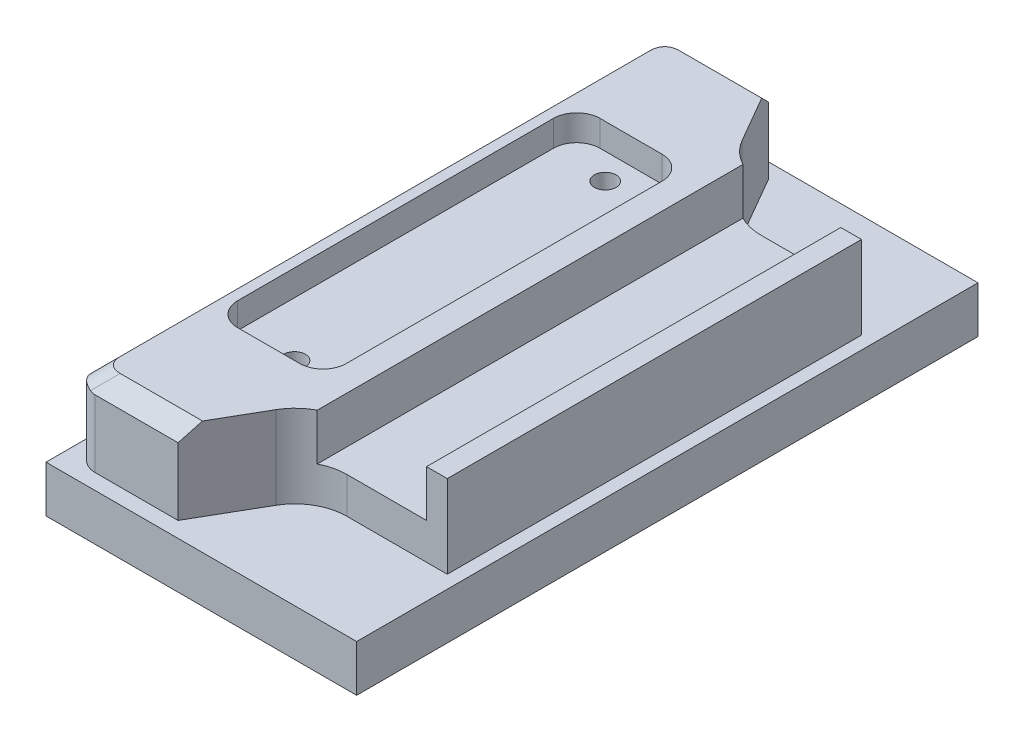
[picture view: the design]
ISO-10303-21;
HEADER;
FILE_DESCRIPTION(('STEP AP214'),'2;1');
FILE_NAME('part.step','',(''),(''),'','','');
FILE_SCHEMA(('AUTOMOTIVE_DESIGN { 1 0 10303 214 1 1 1 1 }'));
ENDSEC;
DATA;
#1=APPLICATION_CONTEXT('core data for automotive mechanical design processes');
#2=APPLICATION_PROTOCOL_DEFINITION('international standard','automotive_design',2000,#1);
#3=PRODUCT_CONTEXT('',#1,'mechanical');
#4=PRODUCT('Part','Part','',(#3));
#5=PRODUCT_RELATED_PRODUCT_CATEGORY('part','',(#4));
#6=PRODUCT_DEFINITION_FORMATION('','',#4);
#7=PRODUCT_DEFINITION_CONTEXT('part definition',#1,'design');
#8=PRODUCT_DEFINITION('design','',#6,#7);
#9=PRODUCT_DEFINITION_SHAPE('','',#8);
#10=(LENGTH_UNIT() NAMED_UNIT(*) SI_UNIT(.MILLI.,.METRE.));
#11=(NAMED_UNIT(*) PLANE_ANGLE_UNIT() SI_UNIT($,.RADIAN.));
#12=(NAMED_UNIT(*) SI_UNIT($,.STERADIAN.) SOLID_ANGLE_UNIT());
#13=UNCERTAINTY_MEASURE_WITH_UNIT(LENGTH_MEASURE(1.E-05),#10,'distance_accuracy_value','');
#14=(GEOMETRIC_REPRESENTATION_CONTEXT(3) GLOBAL_UNCERTAINTY_ASSIGNED_CONTEXT((#13)) GLOBAL_UNIT_ASSIGNED_CONTEXT((#10,
#11,#12)) REPRESENTATION_CONTEXT('',''));
#15=CARTESIAN_POINT('',(0.,0.,0.));
#16=DIRECTION('',(0.,0.,1.));
#17=DIRECTION('',(1.,0.,0.));
#18=AXIS2_PLACEMENT_3D('',#15,#16,#17);
#19=CARTESIAN_POINT('',(0.,16.,57.));
#20=DIRECTION('',(0.,-1.,0.));
#21=DIRECTION('',(1.,0.,0.));
#22=AXIS2_PLACEMENT_3D('',#19,#20,#21);
#23=PLANE('',#22);
#24=DIRECTION('',(1.,0.,0.));
#25=VECTOR('',#24,1.);
#26=CARTESIAN_POINT('',(55.,16.,-40.));
#27=LINE('',#26,#25);
#28=CARTESIAN_POINT('',(51.,16.,-40.));
#29=VERTEX_POINT('',#28);
#30=CARTESIAN_POINT('',(55.,16.,-40.));
#31=VERTEX_POINT('',#30);
#32=EDGE_CURVE('E363',#29,#31,#27,.T.);
#33=ORIENTED_EDGE('',*,*,#32,.F.);
#34=DIRECTION('',(0.,0.,1.));
#35=VECTOR('',#34,1.);
#36=CARTESIAN_POINT('',(51.,16.,-57.));
#37=LINE('',#36,#35);
#38=CARTESIAN_POINT('',(51.,16.,40.));
#39=VERTEX_POINT('',#38);
#40=EDGE_CURVE('E294',#29,#39,#37,.T.);
#41=ORIENTED_EDGE('',*,*,#40,.T.);
#42=DIRECTION('',(-1.,0.,0.));
#43=VECTOR('',#42,1.);
#44=CARTESIAN_POINT('',(55.,16.,40.));
#45=LINE('',#44,#43);
#46=CARTESIAN_POINT('',(55.,16.,40.));
#47=VERTEX_POINT('',#46);
#48=EDGE_CURVE('E375',#47,#39,#45,.T.);
#49=ORIENTED_EDGE('',*,*,#48,.F.);
#50=DIRECTION('',(0.,0.,-1.));
#51=VECTOR('',#50,1.);
#52=CARTESIAN_POINT('',(55.,16.,57.));
#53=LINE('',#52,#51);
#54=EDGE_CURVE('E399',#47,#31,#53,.T.);
#55=ORIENTED_EDGE('',*,*,#54,.T.);
#56=EDGE_LOOP('',(#33,#41,#49,#55));
#57=FACE_BOUND('',#56,.T.);
#58=ADVANCED_FACE('F30',(#57),#23,.F.);
#59=CARTESIAN_POINT('',(0.,0.,57.));
#60=DIRECTION('',(1.,0.,0.));
#61=DIRECTION('',(0.,0.,-1.));
#62=AXIS2_PLACEMENT_3D('',#59,#60,#61);
#63=PLANE('',#62);
#64=DIRECTION('',(0.,0.,-1.));
#65=VECTOR('',#64,1.);
#66=CARTESIAN_POINT('',(0.,0.,57.));
#67=LINE('',#66,#65);
#68=CARTESIAN_POINT('',(0.,0.,53.));
#69=VERTEX_POINT('',#68);
#70=CARTESIAN_POINT('',(0.,0.,-53.));
#71=VERTEX_POINT('',#70);
#72=EDGE_CURVE('E405',#69,#71,#67,.T.);
#73=ORIENTED_EDGE('',*,*,#72,.F.);
#74=DIRECTION('',(0.,-1.,0.));
#75=VECTOR('',#74,1.);
#76=CARTESIAN_POINT('',(0.,0.,53.));
#77=LINE('',#76,#75);
#78=CARTESIAN_POINT('',(0.,13.,53.));
#79=VERTEX_POINT('',#78);
#80=EDGE_CURVE('E461',#69,#79,#77,.F.);
#81=ORIENTED_EDGE('',*,*,#80,.T.);
#82=DIRECTION('',(0.,0.,-1.));
#83=VECTOR('',#82,1.);
#84=CARTESIAN_POINT('',(0.,13.,57.));
#85=LINE('',#84,#83);
#86=CARTESIAN_POINT('',(0.,13.,-53.));
#87=VERTEX_POINT('',#86);
#88=EDGE_CURVE('E419',#79,#87,#85,.T.);
#89=ORIENTED_EDGE('',*,*,#88,.T.);
#90=DIRECTION('',(0.,-1.,0.));
#91=VECTOR('',#90,1.);
#92=CARTESIAN_POINT('',(0.,0.,-53.));
#93=LINE('',#92,#91);
#94=EDGE_CURVE('E458',#87,#71,#93,.T.);
#95=ORIENTED_EDGE('',*,*,#94,.T.);
#96=EDGE_LOOP('',(#73,#81,#89,#95));
#97=FACE_BOUND('',#96,.T.);
#98=ADVANCED_FACE('F32',(#97),#63,.F.);
#99=CARTESIAN_POINT('',(55.,0.,57.));
#100=DIRECTION('',(-1.,0.,0.));
#101=DIRECTION('',(0.,0.,1.));
#102=AXIS2_PLACEMENT_3D('',#99,#100,#101);
#103=PLANE('',#102);
#104=DIRECTION('',(0.,0.,-1.));
#105=VECTOR('',#104,1.);
#106=CARTESIAN_POINT('',(55.,0.,57.));
#107=LINE('',#106,#105);
#108=CARTESIAN_POINT('',(55.,0.,40.));
#109=VERTEX_POINT('',#108);
#110=CARTESIAN_POINT('',(55.,0.,-40.));
#111=VERTEX_POINT('',#110);
#112=EDGE_CURVE('E402',#109,#111,#107,.T.);
#113=ORIENTED_EDGE('',*,*,#112,.T.);
#114=DIRECTION('',(0.,1.,0.));
#115=VECTOR('',#114,1.);
#116=CARTESIAN_POINT('',(55.,0.,-40.));
#117=LINE('',#116,#115);
#118=EDGE_CURVE('E372',#111,#31,#117,.T.);
#119=ORIENTED_EDGE('',*,*,#118,.T.);
#120=ORIENTED_EDGE('',*,*,#54,.F.);
#121=DIRECTION('',(0.,1.,0.));
#122=VECTOR('',#121,1.);
#123=CARTESIAN_POINT('',(55.,0.,40.));
#124=LINE('',#123,#122);
#125=EDGE_CURVE('E389',#109,#47,#124,.T.);
#126=ORIENTED_EDGE('',*,*,#125,.F.);
#127=EDGE_LOOP('',(#113,#119,#120,#126));
#128=FACE_BOUND('',#127,.T.);
#129=ADVANCED_FACE('F549',(#128),#103,.F.);
#130=DIRECTION('',(-1.,0.,0.));
#131=VECTOR('',#130,1.);
#132=CARTESIAN_POINT('',(26.,16.,-35.));
#133=LINE('',#132,#131);
#134=CARTESIAN_POINT('',(21.5,16.,-35.));
#135=VERTEX_POINT('',#134);
#136=CARTESIAN_POINT('',(9.49999999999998,16.,-35.));
#137=VERTEX_POINT('',#136);
#138=EDGE_CURVE('E339',#135,#137,#133,.T.);
#139=ORIENTED_EDGE('',*,*,#138,.F.);
#140=CARTESIAN_POINT('',(21.5,16.,-30.5));
#141=DIRECTION('',(0.,-1.,0.));
#142=DIRECTION('',(1.,0.,0.));
#143=AXIS2_PLACEMENT_3D('',#140,#141,#142);
#144=CIRCLE('',#143,4.5);
#145=CARTESIAN_POINT('',(26.,16.,-30.5));
#146=VERTEX_POINT('',#145);
#147=EDGE_CURVE('E53',#135,#146,#144,.T.);
#148=ORIENTED_EDGE('',*,*,#147,.T.);
#149=DIRECTION('',(0.,0.,-1.));
#150=VECTOR('',#149,1.);
#151=CARTESIAN_POINT('',(26.,16.,35.));
#152=LINE('',#151,#150);
#153=CARTESIAN_POINT('',(26.,16.,30.5));
#154=VERTEX_POINT('',#153);
#155=EDGE_CURVE('E337',#154,#146,#152,.T.);
#156=ORIENTED_EDGE('',*,*,#155,.F.);
#157=CARTESIAN_POINT('',(21.5,16.,30.5));
#158=DIRECTION('',(0.,-1.,0.));
#159=DIRECTION('',(1.,0.,0.));
#160=AXIS2_PLACEMENT_3D('',#157,#158,#159);
#161=CIRCLE('',#160,4.5);
#162=CARTESIAN_POINT('',(21.5,16.,35.));
#163=VERTEX_POINT('',#162);
#164=EDGE_CURVE('E526',#154,#163,#161,.T.);
#165=ORIENTED_EDGE('',*,*,#164,.T.);
#166=DIRECTION('',(1.,0.,0.));
#167=VECTOR('',#166,1.);
#168=CARTESIAN_POINT('',(26.,16.,35.));
#169=LINE('',#168,#167);
#170=CARTESIAN_POINT('',(9.49999999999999,16.,35.));
#171=VERTEX_POINT('',#170);
#172=EDGE_CURVE('E345',#171,#163,#169,.T.);
#173=ORIENTED_EDGE('',*,*,#172,.F.);
#174=CARTESIAN_POINT('',(9.49999999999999,16.,30.5));
#175=DIRECTION('',(0.,-1.,0.));
#176=DIRECTION('',(1.,0.,0.));
#177=AXIS2_PLACEMENT_3D('',#174,#175,#176);
#178=CIRCLE('',#177,4.5);
#179=CARTESIAN_POINT('',(4.99999999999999,16.,30.5));
#180=VERTEX_POINT('',#179);
#181=EDGE_CURVE('E521',#171,#180,#178,.T.);
#182=ORIENTED_EDGE('',*,*,#181,.T.);
#183=DIRECTION('',(0.,0.,1.));
#184=VECTOR('',#183,1.);
#185=CARTESIAN_POINT('',(4.99999999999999,16.,35.));
#186=LINE('',#185,#184);
#187=CARTESIAN_POINT('',(4.99999999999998,16.,-30.5));
#188=VERTEX_POINT('',#187);
#189=EDGE_CURVE('E342',#188,#180,#186,.T.);
#190=ORIENTED_EDGE('',*,*,#189,.F.);
#191=CARTESIAN_POINT('',(9.49999999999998,16.,-30.5));
#192=DIRECTION('',(0.,-1.,0.));
#193=DIRECTION('',(1.,0.,0.));
#194=AXIS2_PLACEMENT_3D('',#191,#192,#193);
#195=CIRCLE('',#194,4.5);
#196=EDGE_CURVE('E523',#188,#137,#195,.T.);
#197=ORIENTED_EDGE('',*,*,#196,.T.);
#198=EDGE_LOOP('',(#139,#148,#156,#165,#173,#182,#190,#197));
#199=FACE_BOUND('',#198,.T.);
#200=CARTESIAN_POINT('',(35.5884572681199,16.,50.));
#201=DIRECTION('',(0.,-1.,0.));
#202=DIRECTION('',(1.,0.,0.));
#203=AXIS2_PLACEMENT_3D('',#200,#201,#202);
#204=CIRCLE('',#203,10.);
#205=CARTESIAN_POINT('',(26.9282032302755,16.,45.));
#206=VERTEX_POINT('',#205);
#207=CARTESIAN_POINT('',(31.,16.,41.1148404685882));
#208=VERTEX_POINT('',#207);
#209=EDGE_CURVE('E443',#206,#208,#204,.T.);
#210=ORIENTED_EDGE('',*,*,#209,.T.);
#211=DIRECTION('',(0.,0.,1.));
#212=VECTOR('',#211,1.);
#213=CARTESIAN_POINT('',(31.,16.,-57.));
#214=LINE('',#213,#212);
#215=CARTESIAN_POINT('',(31.,16.,-41.1148404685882));
#216=VERTEX_POINT('',#215);
#217=EDGE_CURVE('E45',#216,#208,#214,.T.);
#218=ORIENTED_EDGE('',*,*,#217,.F.);
#219=CARTESIAN_POINT('',(35.5884572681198,16.,-50.));
#220=DIRECTION('',(0.,-1.,0.));
#221=DIRECTION('',(1.,0.,0.));
#222=AXIS2_PLACEMENT_3D('',#219,#220,#221);
#223=CIRCLE('',#222,10.);
#224=CARTESIAN_POINT('',(26.9282032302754,16.,-45.));
#225=VERTEX_POINT('',#224);
#226=EDGE_CURVE('E438',#216,#225,#223,.T.);
#227=ORIENTED_EDGE('',*,*,#226,.T.);
#228=DIRECTION('',(0.499999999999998,0.,0.86602540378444));
#229=VECTOR('',#228,1.);
#230=CARTESIAN_POINT('',(29.8149545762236,16.,-40.));
#231=LINE('',#230,#229);
#232=CARTESIAN_POINT('',(21.7320508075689,16.,-54.));
#233=VERTEX_POINT('',#232);
#234=EDGE_CURVE('E360',#233,#225,#231,.T.);
#235=ORIENTED_EDGE('',*,*,#234,.F.);
#236=DIRECTION('',(-1.,0.,0.));
#237=VECTOR('',#236,1.);
#238=CARTESIAN_POINT('',(0.,16.,-54.));
#239=LINE('',#238,#237);
#240=CARTESIAN_POINT('',(5.82842712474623,16.,-54.));
#241=VERTEX_POINT('',#240);
#242=EDGE_CURVE('E411',#233,#241,#239,.T.);
#243=ORIENTED_EDGE('',*,*,#242,.T.);
#244=CARTESIAN_POINT('',(8.65685424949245,16.,-48.3431457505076));
#245=DIRECTION('',(0.,-1.,0.));
#246=DIRECTION('',(0.707106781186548,0.,0.707106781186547));
#247=AXIS2_PLACEMENT_3D('',#244,#245,#246);
#248=ELLIPSE('',#247,6.92820323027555,4.);
#249=CARTESIAN_POINT('',(3.00000000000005,16.,-51.1715728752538));
#250=VERTEX_POINT('',#249);
#251=EDGE_CURVE('E486',#241,#250,#248,.F.);
#252=ORIENTED_EDGE('',*,*,#251,.T.);
#253=DIRECTION('',(0.,0.,1.));
#254=VECTOR('',#253,1.);
#255=CARTESIAN_POINT('',(3.00000000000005,16.,57.));
#256=LINE('',#255,#254);
#257=CARTESIAN_POINT('',(3.00000000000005,16.,51.1715728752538));
#258=VERTEX_POINT('',#257);
#259=EDGE_CURVE('E414',#250,#258,#256,.T.);
#260=ORIENTED_EDGE('',*,*,#259,.T.);
#261=CARTESIAN_POINT('',(8.65685424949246,16.,48.3431457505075));
#262=DIRECTION('',(0.,-1.,0.));
#263=DIRECTION('',(-0.707106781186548,0.,0.707106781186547));
#264=AXIS2_PLACEMENT_3D('',#261,#262,#263);
#265=ELLIPSE('',#264,6.92820323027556,4.);
#266=CARTESIAN_POINT('',(5.82842712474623,16.,54.));
#267=VERTEX_POINT('',#266);
#268=EDGE_CURVE('E484',#258,#267,#265,.F.);
#269=ORIENTED_EDGE('',*,*,#268,.T.);
#270=DIRECTION('',(1.,0.,0.));
#271=VECTOR('',#270,1.);
#272=CARTESIAN_POINT('',(0.,16.,54.));
#273=LINE('',#272,#271);
#274=CARTESIAN_POINT('',(21.7320508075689,16.,54.));
#275=VERTEX_POINT('',#274);
#276=EDGE_CURVE('E417',#267,#275,#273,.T.);
#277=ORIENTED_EDGE('',*,*,#276,.T.);
#278=DIRECTION('',(-0.499999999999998,0.,0.86602540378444));
#279=VECTOR('',#278,1.);
#280=CARTESIAN_POINT('',(29.8149545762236,16.,40.));
#281=LINE('',#280,#279);
#282=EDGE_CURVE('E380',#206,#275,#281,.T.);
#283=ORIENTED_EDGE('',*,*,#282,.F.);
#284=EDGE_LOOP('',(#210,#218,#227,#235,#243,#252,#260,#269,#277,#283));
#285=FACE_BOUND('',#284,.T.);
#286=ADVANCED_FACE('F560',(#199,#285),#23,.F.);
#287=CARTESIAN_POINT('',(0.,16.,57.));
#288=DIRECTION('',(0.,0.,-1.));
#289=DIRECTION('',(-1.,0.,0.));
#290=AXIS2_PLACEMENT_3D('',#287,#288,#289);
#291=PLANE('',#290);
#292=DIRECTION('',(-1.,0.,0.));
#293=VECTOR('',#292,1.);
#294=CARTESIAN_POINT('',(0.,13.,57.));
#295=LINE('',#294,#293);
#296=CARTESIAN_POINT('',(20.,13.,57.));
#297=VERTEX_POINT('',#296);
#298=CARTESIAN_POINT('',(4.,13.,57.));
#299=VERTEX_POINT('',#298);
#300=EDGE_CURVE('E408',#297,#299,#295,.T.);
#301=ORIENTED_EDGE('',*,*,#300,.T.);
#302=DIRECTION('',(0.,-1.,0.));
#303=VECTOR('',#302,1.);
#304=CARTESIAN_POINT('',(4.,16.,57.));
#305=LINE('',#304,#303);
#306=CARTESIAN_POINT('',(4.,0.,57.));
#307=VERTEX_POINT('',#306);
#308=EDGE_CURVE('E449',#299,#307,#305,.T.);
#309=ORIENTED_EDGE('',*,*,#308,.T.);
#310=DIRECTION('',(1.,0.,0.));
#311=VECTOR('',#310,1.);
#312=CARTESIAN_POINT('',(0.,0.,57.));
#313=LINE('',#312,#311);
#314=CARTESIAN_POINT('',(20.,0.,57.));
#315=VERTEX_POINT('',#314);
#316=EDGE_CURVE('E397',#307,#315,#313,.T.);
#317=ORIENTED_EDGE('',*,*,#316,.T.);
#318=DIRECTION('',(0.,1.,0.));
#319=VECTOR('',#318,1.);
#320=CARTESIAN_POINT('',(20.,0.,57.));
#321=LINE('',#320,#319);
#322=EDGE_CURVE('E390',#315,#297,#321,.T.);
#323=ORIENTED_EDGE('',*,*,#322,.T.);
#324=EDGE_LOOP('',(#301,#309,#317,#323));
#325=FACE_BOUND('',#324,.T.);
#326=ADVANCED_FACE('F598',(#325),#291,.F.);
#327=CARTESIAN_POINT('',(0.,16.,-57.));
#328=DIRECTION('',(0.,0.,-1.));
#329=DIRECTION('',(-1.,0.,0.));
#330=AXIS2_PLACEMENT_3D('',#327,#328,#329);
#331=PLANE('',#330);
#332=DIRECTION('',(1.,0.,0.));
#333=VECTOR('',#332,1.);
#334=CARTESIAN_POINT('',(0.,0.,-57.));
#335=LINE('',#334,#333);
#336=CARTESIAN_POINT('',(4.,0.,-57.));
#337=VERTEX_POINT('',#336);
#338=CARTESIAN_POINT('',(20.,0.,-57.));
#339=VERTEX_POINT('',#338);
#340=EDGE_CURVE('E393',#337,#339,#335,.T.);
#341=ORIENTED_EDGE('',*,*,#340,.F.);
#342=DIRECTION('',(0.,-1.,0.));
#343=VECTOR('',#342,1.);
#344=CARTESIAN_POINT('',(4.,13.,-57.));
#345=LINE('',#344,#343);
#346=CARTESIAN_POINT('',(4.,13.,-57.));
#347=VERTEX_POINT('',#346);
#348=EDGE_CURVE('E470',#337,#347,#345,.F.);
#349=ORIENTED_EDGE('',*,*,#348,.T.);
#350=DIRECTION('',(1.,0.,0.));
#351=VECTOR('',#350,1.);
#352=CARTESIAN_POINT('',(55.,13.,-57.));
#353=LINE('',#352,#351);
#354=CARTESIAN_POINT('',(20.,13.,-57.));
#355=VERTEX_POINT('',#354);
#356=EDGE_CURVE('E422',#347,#355,#353,.T.);
#357=ORIENTED_EDGE('',*,*,#356,.T.);
#358=DIRECTION('',(0.,1.,0.));
#359=VECTOR('',#358,1.);
#360=CARTESIAN_POINT('',(20.,0.,-57.));
#361=LINE('',#360,#359);
#362=EDGE_CURVE('E371',#339,#355,#361,.T.);
#363=ORIENTED_EDGE('',*,*,#362,.F.);
#364=EDGE_LOOP('',(#341,#349,#357,#363));
#365=FACE_BOUND('',#364,.T.);
#366=ADVANCED_FACE('F611',(#365),#331,.T.);
#367=CARTESIAN_POINT('',(0.,16.,-54.));
#368=DIRECTION('',(0.,0.70710678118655,-0.707106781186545));
#369=DIRECTION('',(0.,0.707106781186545,0.70710678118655));
#370=AXIS2_PLACEMENT_3D('',#367,#368,#369);
#371=PLANE('',#370);
#372=CARTESIAN_POINT('',(4.,16.9999999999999,-53.));
#373=DIRECTION('',(0.,0.70710678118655,-0.707106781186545));
#374=DIRECTION('',(0.,0.707106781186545,0.70710678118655));
#375=AXIS2_PLACEMENT_3D('',#372,#373,#374);
#376=ELLIPSE('',#375,5.65685424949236,4.);
#377=CARTESIAN_POINT('',(2.9647238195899,13.1362966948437,-56.8637033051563));
#378=VERTEX_POINT('',#377);
#379=EDGE_CURVE('E472',#347,#378,#376,.T.);
#380=ORIENTED_EDGE('',*,*,#379,.T.);
#381=DIRECTION('',(0.577350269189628,0.577350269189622,0.577350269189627));
#382=VECTOR('',#381,1.);
#383=CARTESIAN_POINT('',(3.88561808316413,14.0571909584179,-55.942809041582));
#384=LINE('',#383,#382);
#385=EDGE_CURVE('E482',#378,#241,#384,.T.);
#386=ORIENTED_EDGE('',*,*,#385,.T.);
#387=ORIENTED_EDGE('',*,*,#242,.F.);
#388=DIRECTION('',(0.377964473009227,0.654653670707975,0.65465367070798));
#389=VECTOR('',#388,1.);
#390=CARTESIAN_POINT('',(18.6274721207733,10.6227119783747,-59.3772880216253));
#391=LINE('',#390,#389);
#392=EDGE_CURVE('E426',#355,#233,#391,.T.);
#393=ORIENTED_EDGE('',*,*,#392,.F.);
#394=ORIENTED_EDGE('',*,*,#356,.F.);
#395=EDGE_LOOP('',(#380,#386,#387,#393,#394));
#396=FACE_BOUND('',#395,.T.);
#397=ADVANCED_FACE('F570',(#396),#371,.T.);
#398=CARTESIAN_POINT('',(0.,13.,57.));
#399=DIRECTION('',(0.707106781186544,-0.707106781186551,0.));
#400=DIRECTION('',(0.707106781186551,0.707106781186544,0.));
#401=AXIS2_PLACEMENT_3D('',#398,#399,#400);
#402=PLANE('',#401);
#403=ORIENTED_EDGE('',*,*,#259,.F.);
#404=DIRECTION('',(-0.577350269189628,-0.577350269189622,-0.577350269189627));
#405=VECTOR('',#404,1.);
#406=CARTESIAN_POINT('',(37.0571909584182,50.0571909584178,-17.1143819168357));
#407=LINE('',#406,#405);
#408=CARTESIAN_POINT('',(0.136296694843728,13.1362966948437,-54.0352761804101));
#409=VERTEX_POINT('',#408);
#410=EDGE_CURVE('E477',#250,#409,#407,.T.);
#411=ORIENTED_EDGE('',*,*,#410,.T.);
#412=CARTESIAN_POINT('',(4.,16.9999999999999,-53.));
#413=DIRECTION('',(0.707106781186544,-0.707106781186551,0.));
#414=DIRECTION('',(0.707106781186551,0.707106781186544,0.));
#415=AXIS2_PLACEMENT_3D('',#412,#413,#414);
#416=ELLIPSE('',#415,5.65685424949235,4.);
#417=EDGE_CURVE('E463',#409,#87,#416,.F.);
#418=ORIENTED_EDGE('',*,*,#417,.T.);
#419=ORIENTED_EDGE('',*,*,#88,.F.);
#420=CARTESIAN_POINT('',(4.,16.9999999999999,53.));
#421=DIRECTION('',(0.707106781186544,-0.707106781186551,0.));
#422=DIRECTION('',(-0.707106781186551,-0.707106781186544,0.));
#423=AXIS2_PLACEMENT_3D('',#420,#421,#422);
#424=ELLIPSE('',#423,5.65685424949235,4.);
#425=CARTESIAN_POINT('',(0.13629669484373,13.1362966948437,54.0352761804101));
#426=VERTEX_POINT('',#425);
#427=EDGE_CURVE('E465',#79,#426,#424,.F.);
#428=ORIENTED_EDGE('',*,*,#427,.T.);
#429=DIRECTION('',(0.577350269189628,0.577350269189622,-0.577350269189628));
#430=VECTOR('',#429,1.);
#431=CARTESIAN_POINT('',(-0.942809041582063,12.0571909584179,55.1143819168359));
#432=LINE('',#431,#430);
#433=EDGE_CURVE('E475',#426,#258,#432,.T.);
#434=ORIENTED_EDGE('',*,*,#433,.T.);
#435=EDGE_LOOP('',(#403,#411,#418,#419,#428,#434));
#436=FACE_BOUND('',#435,.T.);
#437=ADVANCED_FACE('F580',(#436),#402,.F.);
#438=CARTESIAN_POINT('',(0.,13.,57.));
#439=DIRECTION('',(0.,-0.707106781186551,-0.707106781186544));
#440=DIRECTION('',(0.,0.707106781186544,-0.707106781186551));
#441=AXIS2_PLACEMENT_3D('',#438,#439,#440);
#442=PLANE('',#441);
#443=ORIENTED_EDGE('',*,*,#276,.F.);
#444=DIRECTION('',(0.577350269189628,0.577350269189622,-0.577350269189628));
#445=VECTOR('',#444,1.);
#446=CARTESIAN_POINT('',(1.88561808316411,12.0571909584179,57.9428090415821));
#447=LINE('',#446,#445);
#448=CARTESIAN_POINT('',(2.9647238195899,13.1362966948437,56.8637033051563));
#449=VERTEX_POINT('',#448);
#450=EDGE_CURVE('E488',#267,#449,#447,.F.);
#451=ORIENTED_EDGE('',*,*,#450,.T.);
#452=CARTESIAN_POINT('',(4.,16.9999999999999,53.));
#453=DIRECTION('',(0.,-0.707106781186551,-0.707106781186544));
#454=DIRECTION('',(0.,-0.707106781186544,0.707106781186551));
#455=AXIS2_PLACEMENT_3D('',#452,#453,#454);
#456=ELLIPSE('',#455,5.65685424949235,4.);
#457=EDGE_CURVE('E468',#449,#299,#456,.F.);
#458=ORIENTED_EDGE('',*,*,#457,.T.);
#459=ORIENTED_EDGE('',*,*,#300,.F.);
#460=DIRECTION('',(0.377964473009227,0.654653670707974,-0.654653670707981));
#461=VECTOR('',#460,1.);
#462=CARTESIAN_POINT('',(17.1428571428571,8.05128340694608,61.948716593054));
#463=LINE('',#462,#461);
#464=EDGE_CURVE('E424',#275,#297,#463,.F.);
#465=ORIENTED_EDGE('',*,*,#464,.F.);
#466=EDGE_LOOP('',(#443,#451,#458,#459,#465));
#467=FACE_BOUND('',#466,.T.);
#468=ADVANCED_FACE('F591',(#467),#442,.F.);
#469=CARTESIAN_POINT('',(29.8149545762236,0.,40.));
#470=DIRECTION('',(-0.86602540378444,0.,-0.499999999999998));
#471=DIRECTION('',(-0.499999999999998,0.,0.86602540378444));
#472=AXIS2_PLACEMENT_3D('',#469,#470,#471);
#473=PLANE('',#472);
#474=DIRECTION('',(-0.499999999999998,0.,0.86602540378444));
#475=VECTOR('',#474,1.);
#476=CARTESIAN_POINT('',(29.8149545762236,0.,40.));
#477=LINE('',#476,#475);
#478=CARTESIAN_POINT('',(26.9282032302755,0.,45.));
#479=VERTEX_POINT('',#478);
#480=EDGE_CURVE('E386',#479,#315,#477,.T.);
#481=ORIENTED_EDGE('',*,*,#480,.F.);
#482=DIRECTION('',(0.,1.,0.));
#483=VECTOR('',#482,1.);
#484=CARTESIAN_POINT('',(26.9282032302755,16.,45.));
#485=LINE('',#484,#483);
#486=EDGE_CURVE('E433',#479,#206,#485,.T.);
#487=ORIENTED_EDGE('',*,*,#486,.T.);
#488=ORIENTED_EDGE('',*,*,#282,.T.);
#489=ORIENTED_EDGE('',*,*,#464,.T.);
#490=ORIENTED_EDGE('',*,*,#322,.F.);
#491=EDGE_LOOP('',(#481,#487,#488,#489,#490));
#492=FACE_BOUND('',#491,.T.);
#493=ADVANCED_FACE('F596',(#492),#473,.F.);
#494=CARTESIAN_POINT('',(55.,0.,40.));
#495=DIRECTION('',(0.,0.,-1.));
#496=DIRECTION('',(-1.,0.,0.));
#497=AXIS2_PLACEMENT_3D('',#494,#495,#496);
#498=PLANE('',#497);
#499=ORIENTED_EDGE('',*,*,#48,.T.);
#500=DIRECTION('',(0.,-1.,0.));
#501=VECTOR('',#500,1.);
#502=CARTESIAN_POINT('',(51.,0.,40.));
#503=LINE('',#502,#501);
#504=CARTESIAN_POINT('',(51.,7.,40.));
#505=VERTEX_POINT('',#504);
#506=EDGE_CURVE('E316',#39,#505,#503,.T.);
#507=ORIENTED_EDGE('',*,*,#506,.T.);
#508=DIRECTION('',(-1.,0.,0.));
#509=VECTOR('',#508,1.);
#510=CARTESIAN_POINT('',(55.,7.,40.));
#511=LINE('',#510,#509);
#512=CARTESIAN_POINT('',(35.5884572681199,7.,40.));
#513=VERTEX_POINT('',#512);
#514=EDGE_CURVE('E307',#505,#513,#511,.T.);
#515=ORIENTED_EDGE('',*,*,#514,.T.);
#516=DIRECTION('',(0.,1.,0.));
#517=VECTOR('',#516,1.);
#518=CARTESIAN_POINT('',(35.5884572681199,0.,40.));
#519=LINE('',#518,#517);
#520=CARTESIAN_POINT('',(35.5884572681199,0.,40.));
#521=VERTEX_POINT('',#520);
#522=EDGE_CURVE('E436',#513,#521,#519,.F.);
#523=ORIENTED_EDGE('',*,*,#522,.T.);
#524=DIRECTION('',(-1.,0.,0.));
#525=VECTOR('',#524,1.);
#526=CARTESIAN_POINT('',(55.,0.,40.));
#527=LINE('',#526,#525);
#528=EDGE_CURVE('E383',#109,#521,#527,.T.);
#529=ORIENTED_EDGE('',*,*,#528,.F.);
#530=ORIENTED_EDGE('',*,*,#125,.T.);
#531=EDGE_LOOP('',(#499,#507,#515,#523,#529,#530));
#532=FACE_BOUND('',#531,.T.);
#533=ADVANCED_FACE('F539',(#532),#498,.F.);
#534=CARTESIAN_POINT('',(55.,0.,-40.));
#535=DIRECTION('',(0.,0.,1.));
#536=DIRECTION('',(1.,0.,0.));
#537=AXIS2_PLACEMENT_3D('',#534,#535,#536);
#538=PLANE('',#537);
#539=DIRECTION('',(1.,0.,0.));
#540=VECTOR('',#539,1.);
#541=CARTESIAN_POINT('',(55.,7.,-40.));
#542=LINE('',#541,#540);
#543=CARTESIAN_POINT('',(35.5884572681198,7.,-40.));
#544=VERTEX_POINT('',#543);
#545=CARTESIAN_POINT('',(51.,7.,-40.));
#546=VERTEX_POINT('',#545);
#547=EDGE_CURVE('E313',#544,#546,#542,.T.);
#548=ORIENTED_EDGE('',*,*,#547,.T.);
#549=DIRECTION('',(0.,1.,0.));
#550=VECTOR('',#549,1.);
#551=CARTESIAN_POINT('',(51.,0.,-40.));
#552=LINE('',#551,#550);
#553=EDGE_CURVE('E11',#546,#29,#552,.T.);
#554=ORIENTED_EDGE('',*,*,#553,.T.);
#555=ORIENTED_EDGE('',*,*,#32,.T.);
#556=ORIENTED_EDGE('',*,*,#118,.F.);
#557=DIRECTION('',(1.,0.,0.));
#558=VECTOR('',#557,1.);
#559=CARTESIAN_POINT('',(55.,0.,-40.));
#560=LINE('',#559,#558);
#561=CARTESIAN_POINT('',(35.5884572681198,0.,-40.));
#562=VERTEX_POINT('',#561);
#563=EDGE_CURVE('E368',#562,#111,#560,.T.);
#564=ORIENTED_EDGE('',*,*,#563,.F.);
#565=DIRECTION('',(0.,1.,0.));
#566=VECTOR('',#565,1.);
#567=CARTESIAN_POINT('',(35.5884572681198,16.,-40.));
#568=LINE('',#567,#566);
#569=EDGE_CURVE('E428',#562,#544,#568,.T.);
#570=ORIENTED_EDGE('',*,*,#569,.T.);
#571=EDGE_LOOP('',(#548,#554,#555,#556,#564,#570));
#572=FACE_BOUND('',#571,.T.);
#573=ADVANCED_FACE('F547',(#572),#538,.F.);
#574=CARTESIAN_POINT('',(29.8149545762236,0.,-40.));
#575=DIRECTION('',(-0.86602540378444,0.,0.499999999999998));
#576=DIRECTION('',(0.499999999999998,0.,0.86602540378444));
#577=AXIS2_PLACEMENT_3D('',#574,#575,#576);
#578=PLANE('',#577);
#579=ORIENTED_EDGE('',*,*,#234,.T.);
#580=DIRECTION('',(0.,1.,0.));
#581=VECTOR('',#580,1.);
#582=CARTESIAN_POINT('',(26.9282032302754,0.,-45.));
#583=LINE('',#582,#581);
#584=CARTESIAN_POINT('',(26.9282032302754,0.,-45.));
#585=VERTEX_POINT('',#584);
#586=EDGE_CURVE('E431',#225,#585,#583,.F.);
#587=ORIENTED_EDGE('',*,*,#586,.T.);
#588=DIRECTION('',(0.499999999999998,0.,0.86602540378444));
#589=VECTOR('',#588,1.);
#590=CARTESIAN_POINT('',(29.8149545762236,0.,-40.));
#591=LINE('',#590,#589);
#592=EDGE_CURVE('E365',#339,#585,#591,.T.);
#593=ORIENTED_EDGE('',*,*,#592,.F.);
#594=ORIENTED_EDGE('',*,*,#362,.T.);
#595=ORIENTED_EDGE('',*,*,#392,.T.);
#596=EDGE_LOOP('',(#579,#587,#593,#594,#595));
#597=FACE_BOUND('',#596,.T.);
#598=ADVANCED_FACE('F564',(#597),#578,.F.);
#599=CARTESIAN_POINT('',(35.5884572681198,0.,-50.));
#600=DIRECTION('',(0.,-1.,0.));
#601=DIRECTION('',(1.,0.,0.));
#602=AXIS2_PLACEMENT_3D('',#599,#600,#601);
#603=CYLINDRICAL_SURFACE('',#602,10.);
#604=DIRECTION('',(0.,-1.,0.));
#605=VECTOR('',#604,1.);
#606=CARTESIAN_POINT('',(31.,0.,-41.1148404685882));
#607=LINE('',#606,#605);
#608=CARTESIAN_POINT('',(31.,7.,-41.1148404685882));
#609=VERTEX_POINT('',#608);
#610=EDGE_CURVE('E298',#216,#609,#607,.T.);
#611=ORIENTED_EDGE('',*,*,#610,.T.);
#612=CARTESIAN_POINT('',(35.5884572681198,7.,-50.));
#613=DIRECTION('',(0.,-1.,0.));
#614=DIRECTION('',(1.,0.,0.));
#615=AXIS2_PLACEMENT_3D('',#612,#613,#614);
#616=CIRCLE('',#615,10.);
#617=EDGE_CURVE('E310',#609,#544,#616,.F.);
#618=ORIENTED_EDGE('',*,*,#617,.T.);
#619=ORIENTED_EDGE('',*,*,#569,.F.);
#620=CARTESIAN_POINT('',(35.5884572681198,0.,-50.));
#621=DIRECTION('',(0.,1.,0.));
#622=DIRECTION('',(-1.,0.,0.));
#623=AXIS2_PLACEMENT_3D('',#620,#621,#622);
#624=CIRCLE('',#623,10.);
#625=EDGE_CURVE('E440',#585,#562,#624,.T.);
#626=ORIENTED_EDGE('',*,*,#625,.F.);
#627=ORIENTED_EDGE('',*,*,#586,.F.);
#628=ORIENTED_EDGE('',*,*,#226,.F.);
#629=EDGE_LOOP('',(#611,#618,#619,#626,#627,#628));
#630=FACE_BOUND('',#629,.T.);
#631=ADVANCED_FACE('F555',(#630),#603,.F.);
#632=CARTESIAN_POINT('',(35.5884572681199,0.,50.));
#633=DIRECTION('',(0.,-1.,0.));
#634=DIRECTION('',(1.,0.,0.));
#635=AXIS2_PLACEMENT_3D('',#632,#633,#634);
#636=CYLINDRICAL_SURFACE('',#635,10.);
#637=ORIENTED_EDGE('',*,*,#522,.F.);
#638=CARTESIAN_POINT('',(35.5884572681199,7.,50.));
#639=DIRECTION('',(0.,-1.,0.));
#640=DIRECTION('',(1.,0.,0.));
#641=AXIS2_PLACEMENT_3D('',#638,#639,#640);
#642=CIRCLE('',#641,10.);
#643=CARTESIAN_POINT('',(31.,7.,41.1148404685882));
#644=VERTEX_POINT('',#643);
#645=EDGE_CURVE('E38',#513,#644,#642,.F.);
#646=ORIENTED_EDGE('',*,*,#645,.T.);
#647=DIRECTION('',(0.,-1.,0.));
#648=VECTOR('',#647,1.);
#649=CARTESIAN_POINT('',(31.,0.,41.1148404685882));
#650=LINE('',#649,#648);
#651=EDGE_CURVE('E528',#644,#208,#650,.F.);
#652=ORIENTED_EDGE('',*,*,#651,.T.);
#653=ORIENTED_EDGE('',*,*,#209,.F.);
#654=ORIENTED_EDGE('',*,*,#486,.F.);
#655=CARTESIAN_POINT('',(35.5884572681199,0.,50.));
#656=DIRECTION('',(0.,1.,0.));
#657=DIRECTION('',(-1.,0.,0.));
#658=AXIS2_PLACEMENT_3D('',#655,#656,#657);
#659=CIRCLE('',#658,10.);
#660=EDGE_CURVE('E446',#521,#479,#659,.T.);
#661=ORIENTED_EDGE('',*,*,#660,.F.);
#662=EDGE_LOOP('',(#637,#646,#652,#653,#654,#661));
#663=FACE_BOUND('',#662,.T.);
#664=ADVANCED_FACE('F532',(#663),#636,.F.);
#665=CARTESIAN_POINT('',(4.,16.,53.));
#666=DIRECTION('',(0.,-1.,0.));
#667=DIRECTION('',(0.,0.,-1.));
#668=AXIS2_PLACEMENT_3D('',#665,#666,#667);
#669=CYLINDRICAL_SURFACE('',#668,4.);
#670=ORIENTED_EDGE('',*,*,#457,.F.);
#671=CARTESIAN_POINT('',(4.,11.3431457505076,53.));
#672=DIRECTION('',(-0.32505758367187,-0.888073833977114,0.32505758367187));
#673=DIRECTION('',(0.627963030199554,-0.459700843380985,-0.627963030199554));
#674=AXIS2_PLACEMENT_3D('',#671,#672,#673);
#675=ELLIPSE('',#674,4.50413000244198,4.);
#676=EDGE_CURVE('E491',#449,#426,#675,.T.);
#677=ORIENTED_EDGE('',*,*,#676,.T.);
#678=ORIENTED_EDGE('',*,*,#427,.F.);
#679=ORIENTED_EDGE('',*,*,#80,.F.);
#680=CARTESIAN_POINT('',(4.,0.,53.));
#681=DIRECTION('',(0.,1.,0.));
#682=DIRECTION('',(-1.,0.,0.));
#683=AXIS2_PLACEMENT_3D('',#680,#681,#682);
#684=CIRCLE('',#683,4.);
#685=EDGE_CURVE('E455',#307,#69,#684,.F.);
#686=ORIENTED_EDGE('',*,*,#685,.F.);
#687=ORIENTED_EDGE('',*,*,#308,.F.);
#688=EDGE_LOOP('',(#670,#677,#678,#679,#686,#687));
#689=FACE_BOUND('',#688,.T.);
#690=ADVANCED_FACE('F604',(#689),#669,.T.);
#691=CARTESIAN_POINT('',(4.,0.,-53.));
#692=DIRECTION('',(0.,1.,0.));
#693=DIRECTION('',(0.,0.,1.));
#694=AXIS2_PLACEMENT_3D('',#691,#692,#693);
#695=CYLINDRICAL_SURFACE('',#694,4.);
#696=ORIENTED_EDGE('',*,*,#417,.F.);
#697=CARTESIAN_POINT('',(3.99999999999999,11.3431457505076,-53.));
#698=DIRECTION('',(0.32505758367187,0.888073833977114,0.325057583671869));
#699=DIRECTION('',(-0.627963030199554,0.459700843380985,-0.627963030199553));
#700=AXIS2_PLACEMENT_3D('',#697,#698,#699);
#701=ELLIPSE('',#700,4.50413000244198,4.);
#702=EDGE_CURVE('E480',#409,#378,#701,.F.);
#703=ORIENTED_EDGE('',*,*,#702,.T.);
#704=ORIENTED_EDGE('',*,*,#379,.F.);
#705=ORIENTED_EDGE('',*,*,#348,.F.);
#706=CARTESIAN_POINT('',(4.,0.,-53.));
#707=DIRECTION('',(0.,1.,0.));
#708=DIRECTION('',(-1.,0.,0.));
#709=AXIS2_PLACEMENT_3D('',#706,#707,#708);
#710=CIRCLE('',#709,4.);
#711=EDGE_CURVE('E452',#71,#337,#710,.F.);
#712=ORIENTED_EDGE('',*,*,#711,.F.);
#713=ORIENTED_EDGE('',*,*,#94,.F.);
#714=EDGE_LOOP('',(#696,#703,#704,#705,#712,#713));
#715=FACE_BOUND('',#714,.T.);
#716=ADVANCED_FACE('F608',(#715),#695,.T.);
#717=CARTESIAN_POINT('',(39.8856180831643,47.2287638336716,-17.1143819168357));
#718=DIRECTION('',(0.577350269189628,0.577350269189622,0.577350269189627));
#719=DIRECTION('',(0.707106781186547,0.,-0.707106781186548));
#720=AXIS2_PLACEMENT_3D('',#717,#718,#719);
#721=CYLINDRICAL_SURFACE('',#720,4.);
#722=ORIENTED_EDGE('',*,*,#251,.F.);
#723=ORIENTED_EDGE('',*,*,#385,.F.);
#724=ORIENTED_EDGE('',*,*,#702,.F.);
#725=ORIENTED_EDGE('',*,*,#410,.F.);
#726=EDGE_LOOP('',(#722,#723,#724,#725));
#727=FACE_BOUND('',#726,.T.);
#728=ADVANCED_FACE('F575',(#727),#721,.T.);
#729=CARTESIAN_POINT('',(1.88561808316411,9.22876383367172,55.1143819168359));
#730=DIRECTION('',(-0.577350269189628,-0.577350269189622,0.577350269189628));
#731=DIRECTION('',(0.707106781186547,0.,0.707106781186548));
#732=AXIS2_PLACEMENT_3D('',#729,#730,#731);
#733=CYLINDRICAL_SURFACE('',#732,4.);
#734=ORIENTED_EDGE('',*,*,#268,.F.);
#735=ORIENTED_EDGE('',*,*,#433,.F.);
#736=ORIENTED_EDGE('',*,*,#676,.F.);
#737=ORIENTED_EDGE('',*,*,#450,.F.);
#738=EDGE_LOOP('',(#734,#735,#736,#737));
#739=FACE_BOUND('',#738,.T.);
#740=ADVANCED_FACE('F586',(#739),#733,.T.);
#741=CARTESIAN_POINT('',(26.,11.,35.));
#742=DIRECTION('',(1.,0.,0.));
#743=DIRECTION('',(0.,0.,-1.));
#744=AXIS2_PLACEMENT_3D('',#741,#742,#743);
#745=PLANE('',#744);
#746=ORIENTED_EDGE('',*,*,#155,.T.);
#747=DIRECTION('',(0.,1.,0.));
#748=VECTOR('',#747,1.);
#749=CARTESIAN_POINT('',(26.,11.,-30.5));
#750=LINE('',#749,#748);
#751=CARTESIAN_POINT('',(26.,11.,-30.5));
#752=VERTEX_POINT('',#751);
#753=EDGE_CURVE('E519',#146,#752,#750,.F.);
#754=ORIENTED_EDGE('',*,*,#753,.T.);
#755=DIRECTION('',(0.,0.,-1.));
#756=VECTOR('',#755,1.);
#757=CARTESIAN_POINT('',(26.,11.,35.));
#758=LINE('',#757,#756);
#759=CARTESIAN_POINT('',(26.,11.,30.5));
#760=VERTEX_POINT('',#759);
#761=EDGE_CURVE('E348',#760,#752,#758,.T.);
#762=ORIENTED_EDGE('',*,*,#761,.F.);
#763=DIRECTION('',(0.,1.,0.));
#764=VECTOR('',#763,1.);
#765=CARTESIAN_POINT('',(26.,16.,30.5));
#766=LINE('',#765,#764);
#767=EDGE_CURVE('E516',#760,#154,#766,.T.);
#768=ORIENTED_EDGE('',*,*,#767,.T.);
#769=EDGE_LOOP('',(#746,#754,#762,#768));
#770=FACE_BOUND('',#769,.T.);
#771=ADVANCED_FACE('F661',(#770),#745,.F.);
#772=CARTESIAN_POINT('',(26.,11.,35.));
#773=DIRECTION('',(0.,0.,1.));
#774=DIRECTION('',(1.,0.,0.));
#775=AXIS2_PLACEMENT_3D('',#772,#773,#774);
#776=PLANE('',#775);
#777=DIRECTION('',(1.,0.,0.));
#778=VECTOR('',#777,1.);
#779=CARTESIAN_POINT('',(26.,11.,35.));
#780=LINE('',#779,#778);
#781=CARTESIAN_POINT('',(9.49999999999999,11.,35.));
#782=VERTEX_POINT('',#781);
#783=CARTESIAN_POINT('',(21.5,11.,35.));
#784=VERTEX_POINT('',#783);
#785=EDGE_CURVE('E357',#782,#784,#780,.T.);
#786=ORIENTED_EDGE('',*,*,#785,.F.);
#787=DIRECTION('',(0.,1.,0.));
#788=VECTOR('',#787,1.);
#789=CARTESIAN_POINT('',(9.49999999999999,16.,35.));
#790=LINE('',#789,#788);
#791=EDGE_CURVE('E495',#782,#171,#790,.T.);
#792=ORIENTED_EDGE('',*,*,#791,.T.);
#793=ORIENTED_EDGE('',*,*,#172,.T.);
#794=DIRECTION('',(0.,1.,0.));
#795=VECTOR('',#794,1.);
#796=CARTESIAN_POINT('',(21.5,11.,35.));
#797=LINE('',#796,#795);
#798=EDGE_CURVE('E493',#163,#784,#797,.F.);
#799=ORIENTED_EDGE('',*,*,#798,.T.);
#800=EDGE_LOOP('',(#786,#792,#793,#799));
#801=FACE_BOUND('',#800,.T.);
#802=ADVANCED_FACE('F652',(#801),#776,.F.);
#803=CARTESIAN_POINT('',(4.99999999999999,11.,35.));
#804=DIRECTION('',(-1.,0.,0.));
#805=DIRECTION('',(0.,0.,1.));
#806=AXIS2_PLACEMENT_3D('',#803,#804,#805);
#807=PLANE('',#806);
#808=ORIENTED_EDGE('',*,*,#189,.T.);
#809=DIRECTION('',(0.,1.,0.));
#810=VECTOR('',#809,1.);
#811=CARTESIAN_POINT('',(4.99999999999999,11.,30.5));
#812=LINE('',#811,#810);
#813=CARTESIAN_POINT('',(4.99999999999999,11.,30.5));
#814=VERTEX_POINT('',#813);
#815=EDGE_CURVE('E501',#180,#814,#812,.F.);
#816=ORIENTED_EDGE('',*,*,#815,.T.);
#817=DIRECTION('',(0.,0.,1.));
#818=VECTOR('',#817,1.);
#819=CARTESIAN_POINT('',(4.99999999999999,11.,35.));
#820=LINE('',#819,#818);
#821=CARTESIAN_POINT('',(4.99999999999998,11.,-30.5));
#822=VERTEX_POINT('',#821);
#823=EDGE_CURVE('E354',#822,#814,#820,.T.);
#824=ORIENTED_EDGE('',*,*,#823,.F.);
#825=DIRECTION('',(0.,1.,0.));
#826=VECTOR('',#825,1.);
#827=CARTESIAN_POINT('',(4.99999999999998,16.,-30.5));
#828=LINE('',#827,#826);
#829=EDGE_CURVE('E498',#822,#188,#828,.T.);
#830=ORIENTED_EDGE('',*,*,#829,.T.);
#831=EDGE_LOOP('',(#808,#816,#824,#830));
#832=FACE_BOUND('',#831,.T.);
#833=ADVANCED_FACE('F644',(#832),#807,.F.);
#834=CARTESIAN_POINT('',(26.,11.,-35.));
#835=DIRECTION('',(0.,0.,-1.));
#836=DIRECTION('',(-1.,0.,0.));
#837=AXIS2_PLACEMENT_3D('',#834,#835,#836);
#838=PLANE('',#837);
#839=ORIENTED_EDGE('',*,*,#138,.T.);
#840=DIRECTION('',(0.,1.,0.));
#841=VECTOR('',#840,1.);
#842=CARTESIAN_POINT('',(9.49999999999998,11.,-35.));
#843=LINE('',#842,#841);
#844=CARTESIAN_POINT('',(9.49999999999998,11.,-35.));
#845=VERTEX_POINT('',#844);
#846=EDGE_CURVE('E514',#137,#845,#843,.F.);
#847=ORIENTED_EDGE('',*,*,#846,.T.);
#848=DIRECTION('',(-1.,0.,0.));
#849=VECTOR('',#848,1.);
#850=CARTESIAN_POINT('',(26.,11.,-35.));
#851=LINE('',#850,#849);
#852=CARTESIAN_POINT('',(21.5,11.,-35.));
#853=VERTEX_POINT('',#852);
#854=EDGE_CURVE('E351',#853,#845,#851,.T.);
#855=ORIENTED_EDGE('',*,*,#854,.F.);
#856=DIRECTION('',(0.,1.,0.));
#857=VECTOR('',#856,1.);
#858=CARTESIAN_POINT('',(21.5,16.,-35.));
#859=LINE('',#858,#857);
#860=EDGE_CURVE('E511',#853,#135,#859,.T.);
#861=ORIENTED_EDGE('',*,*,#860,.T.);
#862=EDGE_LOOP('',(#839,#847,#855,#861));
#863=FACE_BOUND('',#862,.T.);
#864=ADVANCED_FACE('F632',(#863),#838,.F.);
#865=CARTESIAN_POINT('',(26.,11.,-35.));
#866=DIRECTION('',(0.,1.,0.));
#867=DIRECTION('',(0.,0.,1.));
#868=AXIS2_PLACEMENT_3D('',#865,#866,#867);
#869=PLANE('',#868);
#870=CARTESIAN_POINT('',(15.5,11.,30.));
#871=DIRECTION('',(0.,1.,0.));
#872=DIRECTION('',(0.,0.,1.));
#873=AXIS2_PLACEMENT_3D('',#870,#871,#872);
#874=CIRCLE('',#873,2.1);
#875=CARTESIAN_POINT('',(15.5,11.,32.1));
#876=VERTEX_POINT('',#875);
#877=EDGE_CURVE('E325',#876,#876,#874,.T.);
#878=ORIENTED_EDGE('',*,*,#877,.F.);
#879=EDGE_LOOP('',(#878));
#880=FACE_BOUND('',#879,.T.);
#881=CARTESIAN_POINT('',(15.5,11.,-30.));
#882=DIRECTION('',(0.,1.,0.));
#883=DIRECTION('',(0.,0.,1.));
#884=AXIS2_PLACEMENT_3D('',#881,#882,#883);
#885=CIRCLE('',#884,2.1);
#886=CARTESIAN_POINT('',(15.5,11.,-27.9));
#887=VERTEX_POINT('',#886);
#888=EDGE_CURVE('E334',#887,#887,#885,.T.);
#889=ORIENTED_EDGE('',*,*,#888,.F.);
#890=EDGE_LOOP('',(#889));
#891=FACE_BOUND('',#890,.T.);
#892=ORIENTED_EDGE('',*,*,#823,.T.);
#893=CARTESIAN_POINT('',(9.49999999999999,11.,30.5));
#894=DIRECTION('',(0.,1.,0.));
#895=DIRECTION('',(0.,0.,1.));
#896=AXIS2_PLACEMENT_3D('',#893,#894,#895);
#897=CIRCLE('',#896,4.5);
#898=EDGE_CURVE('E509',#814,#782,#897,.T.);
#899=ORIENTED_EDGE('',*,*,#898,.T.);
#900=ORIENTED_EDGE('',*,*,#785,.T.);
#901=CARTESIAN_POINT('',(21.5,11.,30.5));
#902=DIRECTION('',(0.,1.,0.));
#903=DIRECTION('',(0.,0.,1.));
#904=AXIS2_PLACEMENT_3D('',#901,#902,#903);
#905=CIRCLE('',#904,4.5);
#906=EDGE_CURVE('E503',#784,#760,#905,.T.);
#907=ORIENTED_EDGE('',*,*,#906,.T.);
#908=ORIENTED_EDGE('',*,*,#761,.T.);
#909=CARTESIAN_POINT('',(21.5,11.,-30.5));
#910=DIRECTION('',(0.,1.,0.));
#911=DIRECTION('',(0.,0.,1.));
#912=AXIS2_PLACEMENT_3D('',#909,#910,#911);
#913=CIRCLE('',#912,4.5);
#914=EDGE_CURVE('E505',#752,#853,#913,.T.);
#915=ORIENTED_EDGE('',*,*,#914,.T.);
#916=ORIENTED_EDGE('',*,*,#854,.T.);
#917=CARTESIAN_POINT('',(9.49999999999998,11.,-30.5));
#918=DIRECTION('',(0.,1.,0.));
#919=DIRECTION('',(0.,0.,1.));
#920=AXIS2_PLACEMENT_3D('',#917,#918,#919);
#921=CIRCLE('',#920,4.5);
#922=EDGE_CURVE('E507',#845,#822,#921,.T.);
#923=ORIENTED_EDGE('',*,*,#922,.T.);
#924=EDGE_LOOP('',(#892,#899,#900,#907,#908,#915,#916,#923));
#925=FACE_BOUND('',#924,.T.);
#926=ADVANCED_FACE('F641',(#880,#891,#925),#869,.T.);
#927=CARTESIAN_POINT('',(9.49999999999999,11.,30.5));
#928=DIRECTION('',(0.,-1.,0.));
#929=DIRECTION('',(1.,0.,0.));
#930=AXIS2_PLACEMENT_3D('',#927,#928,#929);
#931=CYLINDRICAL_SURFACE('',#930,4.5);
#932=ORIENTED_EDGE('',*,*,#898,.F.);
#933=ORIENTED_EDGE('',*,*,#815,.F.);
#934=ORIENTED_EDGE('',*,*,#181,.F.);
#935=ORIENTED_EDGE('',*,*,#791,.F.);
#936=EDGE_LOOP('',(#932,#933,#934,#935));
#937=FACE_BOUND('',#936,.T.);
#938=ADVANCED_FACE('F647',(#937),#931,.F.);
#939=CARTESIAN_POINT('',(9.49999999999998,11.,-30.5));
#940=DIRECTION('',(0.,-1.,0.));
#941=DIRECTION('',(1.,0.,0.));
#942=AXIS2_PLACEMENT_3D('',#939,#940,#941);
#943=CYLINDRICAL_SURFACE('',#942,4.5);
#944=ORIENTED_EDGE('',*,*,#922,.F.);
#945=ORIENTED_EDGE('',*,*,#846,.F.);
#946=ORIENTED_EDGE('',*,*,#196,.F.);
#947=ORIENTED_EDGE('',*,*,#829,.F.);
#948=EDGE_LOOP('',(#944,#945,#946,#947));
#949=FACE_BOUND('',#948,.T.);
#950=ADVANCED_FACE('F637',(#949),#943,.F.);
#951=CARTESIAN_POINT('',(21.5,11.,-30.5));
#952=DIRECTION('',(0.,-1.,0.));
#953=DIRECTION('',(1.,0.,0.));
#954=AXIS2_PLACEMENT_3D('',#951,#952,#953);
#955=CYLINDRICAL_SURFACE('',#954,4.5);
#956=ORIENTED_EDGE('',*,*,#914,.F.);
#957=ORIENTED_EDGE('',*,*,#753,.F.);
#958=ORIENTED_EDGE('',*,*,#147,.F.);
#959=ORIENTED_EDGE('',*,*,#860,.F.);
#960=EDGE_LOOP('',(#956,#957,#958,#959));
#961=FACE_BOUND('',#960,.T.);
#962=ADVANCED_FACE('F664',(#961),#955,.F.);
#963=CARTESIAN_POINT('',(21.5,11.,30.5));
#964=DIRECTION('',(0.,-1.,0.));
#965=DIRECTION('',(1.,0.,0.));
#966=AXIS2_PLACEMENT_3D('',#963,#964,#965);
#967=CYLINDRICAL_SURFACE('',#966,4.5);
#968=ORIENTED_EDGE('',*,*,#906,.F.);
#969=ORIENTED_EDGE('',*,*,#798,.F.);
#970=ORIENTED_EDGE('',*,*,#164,.F.);
#971=ORIENTED_EDGE('',*,*,#767,.F.);
#972=EDGE_LOOP('',(#968,#969,#970,#971));
#973=FACE_BOUND('',#972,.T.);
#974=ADVANCED_FACE('F656',(#973),#967,.F.);
#975=CARTESIAN_POINT('',(15.5,0.,-30.));
#976=DIRECTION('',(0.,-1.,0.));
#977=DIRECTION('',(0.,0.,-1.));
#978=AXIS2_PLACEMENT_3D('',#975,#976,#977);
#979=CYLINDRICAL_SURFACE('',#978,2.1);
#980=CARTESIAN_POINT('',(15.5,5.,-30.));
#981=DIRECTION('',(0.,-1.,0.));
#982=DIRECTION('',(0.,0.,-1.));
#983=AXIS2_PLACEMENT_3D('',#980,#981,#982);
#984=CIRCLE('',#983,2.1);
#985=CARTESIAN_POINT('',(15.5,5.,-32.1));
#986=VERTEX_POINT('',#985);
#987=EDGE_CURVE('E328',#986,#986,#984,.T.);
#988=ORIENTED_EDGE('',*,*,#987,.T.);
#989=EDGE_LOOP('',(#988));
#990=FACE_BOUND('',#989,.T.);
#991=ORIENTED_EDGE('',*,*,#888,.T.);
#992=EDGE_LOOP('',(#991));
#993=FACE_BOUND('',#992,.T.);
#994=ADVANCED_FACE('F671',(#990,#993),#979,.F.);
#995=CARTESIAN_POINT('',(15.5,0.,-30.));
#996=DIRECTION('',(0.,-1.,0.));
#997=DIRECTION('',(0.,0.,-1.));
#998=AXIS2_PLACEMENT_3D('',#995,#996,#997);
#999=CYLINDRICAL_SURFACE('',#998,3.6);
#1000=CARTESIAN_POINT('',(15.5,5.,-30.));
#1001=DIRECTION('',(0.,-1.,0.));
#1002=DIRECTION('',(0.,0.,-1.));
#1003=AXIS2_PLACEMENT_3D('',#1000,#1001,#1002);
#1004=CIRCLE('',#1003,3.6);
#1005=CARTESIAN_POINT('',(15.5,5.,-33.6));
#1006=VERTEX_POINT('',#1005);
#1007=EDGE_CURVE('E331',#1006,#1006,#1004,.T.);
#1008=ORIENTED_EDGE('',*,*,#1007,.F.);
#1009=EDGE_LOOP('',(#1008));
#1010=FACE_BOUND('',#1009,.T.);
#1011=CARTESIAN_POINT('',(15.5,0.,-30.));
#1012=DIRECTION('',(0.,1.,0.));
#1013=DIRECTION('',(-1.,0.,0.));
#1014=AXIS2_PLACEMENT_3D('',#1011,#1012,#1013);
#1015=CIRCLE('',#1014,3.6);
#1016=CARTESIAN_POINT('',(11.9,0.,-30.));
#1017=VERTEX_POINT('',#1016);
#1018=EDGE_CURVE('E291',#1017,#1017,#1015,.F.);
#1019=ORIENTED_EDGE('',*,*,#1018,.T.);
#1020=EDGE_LOOP('',(#1019));
#1021=FACE_BOUND('',#1020,.T.);
#1022=ADVANCED_FACE('F810',(#1010,#1021),#999,.F.);
#1023=CARTESIAN_POINT('',(17.6,5.,-30.));
#1024=DIRECTION('',(0.,1.,0.));
#1025=DIRECTION('',(0.,0.,1.));
#1026=AXIS2_PLACEMENT_3D('',#1023,#1024,#1025);
#1027=PLANE('',#1026);
#1028=ORIENTED_EDGE('',*,*,#987,.F.);
#1029=EDGE_LOOP('',(#1028));
#1030=FACE_BOUND('',#1029,.T.);
#1031=ORIENTED_EDGE('',*,*,#1007,.T.);
#1032=EDGE_LOOP('',(#1031));
#1033=FACE_BOUND('',#1032,.T.);
#1034=ADVANCED_FACE('F819',(#1030,#1033),#1027,.F.);
#1035=CARTESIAN_POINT('',(15.5,0.,30.));
#1036=DIRECTION('',(0.,-1.,0.));
#1037=DIRECTION('',(0.,0.,-1.));
#1038=AXIS2_PLACEMENT_3D('',#1035,#1036,#1037);
#1039=CYLINDRICAL_SURFACE('',#1038,2.1);
#1040=CARTESIAN_POINT('',(15.5,5.,30.));
#1041=DIRECTION('',(0.,-1.,0.));
#1042=DIRECTION('',(0.,0.,-1.));
#1043=AXIS2_PLACEMENT_3D('',#1040,#1041,#1042);
#1044=CIRCLE('',#1043,2.1);
#1045=CARTESIAN_POINT('',(15.5,5.,27.9));
#1046=VERTEX_POINT('',#1045);
#1047=EDGE_CURVE('E322',#1046,#1046,#1044,.T.);
#1048=ORIENTED_EDGE('',*,*,#1047,.T.);
#1049=EDGE_LOOP('',(#1048));
#1050=FACE_BOUND('',#1049,.T.);
#1051=ORIENTED_EDGE('',*,*,#877,.T.);
#1052=EDGE_LOOP('',(#1051));
#1053=FACE_BOUND('',#1052,.T.);
#1054=ADVANCED_FACE('F827',(#1050,#1053),#1039,.F.);
#1055=CARTESIAN_POINT('',(17.6,5.,30.));
#1056=DIRECTION('',(0.,1.,0.));
#1057=DIRECTION('',(0.,0.,1.));
#1058=AXIS2_PLACEMENT_3D('',#1055,#1056,#1057);
#1059=PLANE('',#1058);
#1060=ORIENTED_EDGE('',*,*,#1047,.F.);
#1061=EDGE_LOOP('',(#1060));
#1062=FACE_BOUND('',#1061,.T.);
#1063=CARTESIAN_POINT('',(15.5,5.,30.));
#1064=DIRECTION('',(0.,-1.,0.));
#1065=DIRECTION('',(0.,0.,-1.));
#1066=AXIS2_PLACEMENT_3D('',#1063,#1064,#1065);
#1067=CIRCLE('',#1066,3.6);
#1068=CARTESIAN_POINT('',(15.5,5.,26.4));
#1069=VERTEX_POINT('',#1068);
#1070=EDGE_CURVE('E319',#1069,#1069,#1067,.T.);
#1071=ORIENTED_EDGE('',*,*,#1070,.T.);
#1072=EDGE_LOOP('',(#1071));
#1073=FACE_BOUND('',#1072,.T.);
#1074=ADVANCED_FACE('F837',(#1062,#1073),#1059,.F.);
#1075=CARTESIAN_POINT('',(15.5,0.,30.));
#1076=DIRECTION('',(0.,-1.,0.));
#1077=DIRECTION('',(0.,0.,-1.));
#1078=AXIS2_PLACEMENT_3D('',#1075,#1076,#1077);
#1079=CYLINDRICAL_SURFACE('',#1078,3.6);
#1080=ORIENTED_EDGE('',*,*,#1070,.F.);
#1081=EDGE_LOOP('',(#1080));
#1082=FACE_BOUND('',#1081,.T.);
#1083=CARTESIAN_POINT('',(15.5,0.,30.));
#1084=DIRECTION('',(0.,1.,0.));
#1085=DIRECTION('',(-1.,0.,0.));
#1086=AXIS2_PLACEMENT_3D('',#1083,#1084,#1085);
#1087=CIRCLE('',#1086,3.6);
#1088=CARTESIAN_POINT('',(11.9,0.,30.));
#1089=VERTEX_POINT('',#1088);
#1090=EDGE_CURVE('E265',#1089,#1089,#1087,.F.);
#1091=ORIENTED_EDGE('',*,*,#1090,.T.);
#1092=EDGE_LOOP('',(#1091));
#1093=FACE_BOUND('',#1092,.T.);
#1094=ADVANCED_FACE('F844',(#1082,#1093),#1079,.F.);
#1095=CARTESIAN_POINT('',(51.,16.,-57.));
#1096=DIRECTION('',(1.,0.,0.));
#1097=DIRECTION('',(0.,0.,-1.));
#1098=AXIS2_PLACEMENT_3D('',#1095,#1096,#1097);
#1099=PLANE('',#1098);
#1100=ORIENTED_EDGE('',*,*,#40,.F.);
#1101=ORIENTED_EDGE('',*,*,#553,.F.);
#1102=DIRECTION('',(0.,0.,1.));
#1103=VECTOR('',#1102,1.);
#1104=CARTESIAN_POINT('',(51.,7.,-57.));
#1105=LINE('',#1104,#1103);
#1106=EDGE_CURVE('E295',#546,#505,#1105,.T.);
#1107=ORIENTED_EDGE('',*,*,#1106,.T.);
#1108=ORIENTED_EDGE('',*,*,#506,.F.);
#1109=EDGE_LOOP('',(#1100,#1101,#1107,#1108));
#1110=FACE_BOUND('',#1109,.T.);
#1111=ADVANCED_FACE('F542',(#1110),#1099,.F.);
#1112=CARTESIAN_POINT('',(51.,7.,-57.));
#1113=DIRECTION('',(0.,-1.,0.));
#1114=DIRECTION('',(1.,0.,0.));
#1115=AXIS2_PLACEMENT_3D('',#1112,#1113,#1114);
#1116=PLANE('',#1115);
#1117=ORIENTED_EDGE('',*,*,#617,.F.);
#1118=DIRECTION('',(0.,0.,1.));
#1119=VECTOR('',#1118,1.);
#1120=CARTESIAN_POINT('',(31.,7.,-57.));
#1121=LINE('',#1120,#1119);
#1122=EDGE_CURVE('E299',#609,#644,#1121,.T.);
#1123=ORIENTED_EDGE('',*,*,#1122,.T.);
#1124=ORIENTED_EDGE('',*,*,#645,.F.);
#1125=ORIENTED_EDGE('',*,*,#514,.F.);
#1126=ORIENTED_EDGE('',*,*,#1106,.F.);
#1127=ORIENTED_EDGE('',*,*,#547,.F.);
#1128=EDGE_LOOP('',(#1117,#1123,#1124,#1125,#1126,#1127));
#1129=FACE_BOUND('',#1128,.T.);
#1130=ADVANCED_FACE('F535',(#1129),#1116,.F.);
#1131=CARTESIAN_POINT('',(31.,16.,-57.));
#1132=DIRECTION('',(-1.,0.,0.));
#1133=DIRECTION('',(0.,0.,1.));
#1134=AXIS2_PLACEMENT_3D('',#1131,#1132,#1133);
#1135=PLANE('',#1134);
#1136=ORIENTED_EDGE('',*,*,#217,.T.);
#1137=ORIENTED_EDGE('',*,*,#651,.F.);
#1138=ORIENTED_EDGE('',*,*,#1122,.F.);
#1139=ORIENTED_EDGE('',*,*,#610,.F.);
#1140=EDGE_LOOP('',(#1136,#1137,#1138,#1139));
#1141=FACE_BOUND('',#1140,.T.);
#1142=ADVANCED_FACE('F558',(#1141),#1135,.F.);
#1143=CARTESIAN_POINT('',(-2.5,0.,60.));
#1144=DIRECTION('',(0.,1.,0.));
#1145=DIRECTION('',(-1.,0.,0.));
#1146=AXIS2_PLACEMENT_3D('',#1143,#1144,#1145);
#1147=PLANE('',#1146);
#1148=ORIENTED_EDGE('',*,*,#1090,.F.);
#1149=EDGE_LOOP('',(#1148));
#1150=FACE_BOUND('',#1149,.T.);
#1151=ADVANCED_FACE('F871',(#1150),#1147,.T.);
#1152=ORIENTED_EDGE('',*,*,#1018,.F.);
#1153=EDGE_LOOP('',(#1152));
#1154=FACE_BOUND('',#1153,.T.);
#1155=ADVANCED_FACE('F878',(#1154),#1147,.T.);
#1156=DIRECTION('',(0.,0.,-1.));
#1157=VECTOR('',#1156,1.);
#1158=CARTESIAN_POINT('',(-2.5,0.,-60.));
#1159=LINE('',#1158,#1157);
#1160=CARTESIAN_POINT('',(-2.5,0.,60.));
#1161=VERTEX_POINT('',#1160);
#1162=CARTESIAN_POINT('',(-2.5,0.,-60.));
#1163=VERTEX_POINT('',#1162);
#1164=EDGE_CURVE('E252',#1161,#1163,#1159,.T.);
#1165=ORIENTED_EDGE('',*,*,#1164,.F.);
#1166=DIRECTION('',(-1.,0.,0.));
#1167=VECTOR('',#1166,1.);
#1168=CARTESIAN_POINT('',(-2.5,0.,60.));
#1169=LINE('',#1168,#1167);
#1170=CARTESIAN_POINT('',(57.5,0.,60.));
#1171=VERTEX_POINT('',#1170);
#1172=EDGE_CURVE('E275',#1171,#1161,#1169,.T.);
#1173=ORIENTED_EDGE('',*,*,#1172,.F.);
#1174=DIRECTION('',(0.,0.,1.));
#1175=VECTOR('',#1174,1.);
#1176=CARTESIAN_POINT('',(57.5,0.,-60.));
#1177=LINE('',#1176,#1175);
#1178=CARTESIAN_POINT('',(57.5,0.,-60.));
#1179=VERTEX_POINT('',#1178);
#1180=EDGE_CURVE('E253',#1179,#1171,#1177,.T.);
#1181=ORIENTED_EDGE('',*,*,#1180,.F.);
#1182=DIRECTION('',(1.,0.,0.));
#1183=VECTOR('',#1182,1.);
#1184=CARTESIAN_POINT('',(-2.5,0.,-60.));
#1185=LINE('',#1184,#1183);
#1186=EDGE_CURVE('E246',#1163,#1179,#1185,.T.);
#1187=ORIENTED_EDGE('',*,*,#1186,.F.);
#1188=EDGE_LOOP('',(#1165,#1173,#1181,#1187));
#1189=FACE_BOUND('',#1188,.T.);
#1190=ORIENTED_EDGE('',*,*,#528,.T.);
#1191=ORIENTED_EDGE('',*,*,#660,.T.);
#1192=ORIENTED_EDGE('',*,*,#480,.T.);
#1193=ORIENTED_EDGE('',*,*,#316,.F.);
#1194=ORIENTED_EDGE('',*,*,#685,.T.);
#1195=ORIENTED_EDGE('',*,*,#72,.T.);
#1196=ORIENTED_EDGE('',*,*,#711,.T.);
#1197=ORIENTED_EDGE('',*,*,#340,.T.);
#1198=ORIENTED_EDGE('',*,*,#592,.T.);
#1199=ORIENTED_EDGE('',*,*,#625,.T.);
#1200=ORIENTED_EDGE('',*,*,#563,.T.);
#1201=ORIENTED_EDGE('',*,*,#112,.F.);
#1202=EDGE_LOOP('',(#1190,#1191,#1192,#1193,#1194,#1195,#1196,#1197,#1198,#1199,#1200,#1201));
#1203=FACE_BOUND('',#1202,.T.);
#1204=ADVANCED_FACE('F248',(#1189,#1203),#1147,.T.);
#1205=CARTESIAN_POINT('',(-2.5,-9.,-60.));
#1206=DIRECTION('',(1.,0.,0.));
#1207=DIRECTION('',(0.,1.,0.));
#1208=AXIS2_PLACEMENT_3D('',#1205,#1206,#1207);
#1209=PLANE('',#1208);
#1210=ORIENTED_EDGE('',*,*,#1164,.T.);
#1211=DIRECTION('',(0.,1.,0.));
#1212=VECTOR('',#1211,1.);
#1213=CARTESIAN_POINT('',(-2.5,-9.,-60.));
#1214=LINE('',#1213,#1212);
#1215=CARTESIAN_POINT('',(-2.5,-9.,-60.));
#1216=VERTEX_POINT('',#1215);
#1217=EDGE_CURVE('E259',#1216,#1163,#1214,.T.);
#1218=ORIENTED_EDGE('',*,*,#1217,.F.);
#1219=DIRECTION('',(0.,0.,-1.));
#1220=VECTOR('',#1219,1.);
#1221=CARTESIAN_POINT('',(-2.5,-9.,-60.));
#1222=LINE('',#1221,#1220);
#1223=CARTESIAN_POINT('',(-2.5,-9.,60.));
#1224=VERTEX_POINT('',#1223);
#1225=EDGE_CURVE('E277',#1224,#1216,#1222,.T.);
#1226=ORIENTED_EDGE('',*,*,#1225,.F.);
#1227=DIRECTION('',(0.,1.,0.));
#1228=VECTOR('',#1227,1.);
#1229=CARTESIAN_POINT('',(-2.5,-9.,60.));
#1230=LINE('',#1229,#1228);
#1231=EDGE_CURVE('E271',#1224,#1161,#1230,.T.);
#1232=ORIENTED_EDGE('',*,*,#1231,.T.);
#1233=EDGE_LOOP('',(#1210,#1218,#1226,#1232));
#1234=FACE_BOUND('',#1233,.T.);
#1235=ADVANCED_FACE('F269',(#1234),#1209,.F.);
#1236=CARTESIAN_POINT('',(-2.5,-9.,-60.));
#1237=DIRECTION('',(0.,0.,1.));
#1238=DIRECTION('',(1.,0.,0.));
#1239=AXIS2_PLACEMENT_3D('',#1236,#1237,#1238);
#1240=PLANE('',#1239);
#1241=ORIENTED_EDGE('',*,*,#1186,.T.);
#1242=DIRECTION('',(0.,1.,0.));
#1243=VECTOR('',#1242,1.);
#1244=CARTESIAN_POINT('',(57.5,-9.,-60.));
#1245=LINE('',#1244,#1243);
#1246=CARTESIAN_POINT('',(57.5,-9.,-60.));
#1247=VERTEX_POINT('',#1246);
#1248=EDGE_CURVE('E266',#1247,#1179,#1245,.T.);
#1249=ORIENTED_EDGE('',*,*,#1248,.F.);
#1250=DIRECTION('',(1.,0.,0.));
#1251=VECTOR('',#1250,1.);
#1252=CARTESIAN_POINT('',(-2.5,-9.,-60.));
#1253=LINE('',#1252,#1251);
#1254=EDGE_CURVE('E261',#1216,#1247,#1253,.T.);
#1255=ORIENTED_EDGE('',*,*,#1254,.F.);
#1256=ORIENTED_EDGE('',*,*,#1217,.T.);
#1257=EDGE_LOOP('',(#1241,#1249,#1255,#1256));
#1258=FACE_BOUND('',#1257,.T.);
#1259=ADVANCED_FACE('F260',(#1258),#1240,.F.);
#1260=CARTESIAN_POINT('',(57.5,-9.,-60.));
#1261=DIRECTION('',(-1.,0.,0.));
#1262=DIRECTION('',(0.,-1.,0.));
#1263=AXIS2_PLACEMENT_3D('',#1260,#1261,#1262);
#1264=PLANE('',#1263);
#1265=ORIENTED_EDGE('',*,*,#1180,.T.);
#1266=DIRECTION('',(0.,1.,0.));
#1267=VECTOR('',#1266,1.);
#1268=CARTESIAN_POINT('',(57.5,-9.,60.));
#1269=LINE('',#1268,#1267);
#1270=CARTESIAN_POINT('',(57.5,-9.,60.));
#1271=VERTEX_POINT('',#1270);
#1272=EDGE_CURVE('E285',#1271,#1171,#1269,.T.);
#1273=ORIENTED_EDGE('',*,*,#1272,.F.);
#1274=DIRECTION('',(0.,0.,1.));
#1275=VECTOR('',#1274,1.);
#1276=CARTESIAN_POINT('',(57.5,-9.,-60.));
#1277=LINE('',#1276,#1275);
#1278=EDGE_CURVE('E280',#1247,#1271,#1277,.T.);
#1279=ORIENTED_EDGE('',*,*,#1278,.F.);
#1280=ORIENTED_EDGE('',*,*,#1248,.T.);
#1281=EDGE_LOOP('',(#1265,#1273,#1279,#1280));
#1282=FACE_BOUND('',#1281,.T.);
#1283=ADVANCED_FACE('F903',(#1282),#1264,.F.);
#1284=CARTESIAN_POINT('',(-2.5,-9.,60.));
#1285=DIRECTION('',(0.,0.,-1.));
#1286=DIRECTION('',(-1.,0.,0.));
#1287=AXIS2_PLACEMENT_3D('',#1284,#1285,#1286);
#1288=PLANE('',#1287);
#1289=ORIENTED_EDGE('',*,*,#1172,.T.);
#1290=ORIENTED_EDGE('',*,*,#1231,.F.);
#1291=DIRECTION('',(-1.,0.,0.));
#1292=VECTOR('',#1291,1.);
#1293=CARTESIAN_POINT('',(-2.5,-9.,60.));
#1294=LINE('',#1293,#1292);
#1295=EDGE_CURVE('E282',#1271,#1224,#1294,.T.);
#1296=ORIENTED_EDGE('',*,*,#1295,.F.);
#1297=ORIENTED_EDGE('',*,*,#1272,.T.);
#1298=EDGE_LOOP('',(#1289,#1290,#1296,#1297));
#1299=FACE_BOUND('',#1298,.T.);
#1300=ADVANCED_FACE('F910',(#1299),#1288,.F.);
#1301=CARTESIAN_POINT('',(-2.5,-9.,60.));
#1302=DIRECTION('',(0.,1.,0.));
#1303=DIRECTION('',(-1.,0.,0.));
#1304=AXIS2_PLACEMENT_3D('',#1301,#1302,#1303);
#1305=PLANE('',#1304);
#1306=ORIENTED_EDGE('',*,*,#1225,.T.);
#1307=ORIENTED_EDGE('',*,*,#1254,.T.);
#1308=ORIENTED_EDGE('',*,*,#1278,.T.);
#1309=ORIENTED_EDGE('',*,*,#1295,.T.);
#1310=EDGE_LOOP('',(#1306,#1307,#1308,#1309));
#1311=FACE_BOUND('',#1310,.T.);
#1312=ADVANCED_FACE('F918',(#1311),#1305,.F.);
#1313=CLOSED_SHELL('',(#58,#98,#129,#286,#326,#366,#397,#437,#468,#493,#533,#573,#598,#631,#664,
#690,#716,#728,#740,#771,#802,#833,#864,#926,#938,#950,#962,#974,#994,#1022,#1034,#1054,#1074,
#1094,#1111,#1130,#1142,#1151,#1155,#1204,#1235,#1259,#1283,#1300,#1312));
#1314=MANIFOLD_SOLID_BREP('B2',#1313);
#1315=ADVANCED_BREP_SHAPE_REPRESENTATION('',(#18,#1314),#14);
#1316=SHAPE_DEFINITION_REPRESENTATION(#9,#1315);
ENDSEC;
END-ISO-10303-21;
